VERSION 5.8 ;
BUSBITCHARS "[]" ;
DIVIDERCHAR "/" ;
UNITS
    DATABASE MICRONS 1000 ;
END UNITS

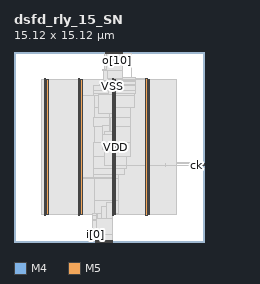
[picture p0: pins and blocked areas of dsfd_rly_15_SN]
MACRO dsfd_rly_15_SN
  FOREIGN dsfd_rly_15_SN 0 0 ;
  CLASS BLOCK ;
  SIZE 15.12 BY 15.12 ;
  PIN ck
    DIRECTION INPUT ;
    USE SIGNAL ;
    PORT
      LAYER M4 ;
        RECT  15.036 6.096 15.12 6.12 ;
    END
  END ck
  PIN i[0]
    DIRECTION INPUT ;
    USE SIGNAL ;
    PORT
      LAYER M5 ;
        RECT  6.48 0 6.504 0.084 ;
    END
  END i[0]
  PIN i[10]
    DIRECTION INPUT ;
    USE SIGNAL ;
    PORT
      LAYER M5 ;
        RECT  7.44 0 7.464 0.084 ;
    END
  END i[10]
  PIN i[11]
    DIRECTION INPUT ;
    USE SIGNAL ;
    PORT
      LAYER M5 ;
        RECT  7.536 0 7.56 0.084 ;
    END
  END i[11]
  PIN i[12]
    DIRECTION INPUT ;
    USE SIGNAL ;
    PORT
      LAYER M5 ;
        RECT  7.632 0 7.656 0.084 ;
    END
  END i[12]
  PIN i[13]
    DIRECTION INPUT ;
    USE SIGNAL ;
    PORT
      LAYER M5 ;
        RECT  7.728 0 7.752 0.084 ;
    END
  END i[13]
  PIN i[14]
    DIRECTION INPUT ;
    USE SIGNAL ;
    PORT
      LAYER M5 ;
        RECT  7.824 0 7.848 0.084 ;
    END
  END i[14]
  PIN i[1]
    DIRECTION INPUT ;
    USE SIGNAL ;
    PORT
      LAYER M5 ;
        RECT  6.576 0 6.6 0.084 ;
    END
  END i[1]
  PIN i[2]
    DIRECTION INPUT ;
    USE SIGNAL ;
    PORT
      LAYER M5 ;
        RECT  6.672 0 6.696 0.084 ;
    END
  END i[2]
  PIN i[3]
    DIRECTION INPUT ;
    USE SIGNAL ;
    PORT
      LAYER M5 ;
        RECT  6.768 0 6.792 0.084 ;
    END
  END i[3]
  PIN i[4]
    DIRECTION INPUT ;
    USE SIGNAL ;
    PORT
      LAYER M5 ;
        RECT  6.864 0 6.888 0.084 ;
    END
  END i[4]
  PIN i[5]
    DIRECTION INPUT ;
    USE SIGNAL ;
    PORT
      LAYER M5 ;
        RECT  6.96 0 6.984 0.084 ;
    END
  END i[5]
  PIN i[6]
    DIRECTION INPUT ;
    USE SIGNAL ;
    PORT
      LAYER M5 ;
        RECT  7.056 0 7.08 0.084 ;
    END
  END i[6]
  PIN i[7]
    DIRECTION INPUT ;
    USE SIGNAL ;
    PORT
      LAYER M5 ;
        RECT  7.152 0 7.176 0.084 ;
    END
  END i[7]
  PIN i[8]
    DIRECTION INPUT ;
    USE SIGNAL ;
    PORT
      LAYER M5 ;
        RECT  7.248 0 7.272 0.084 ;
    END
  END i[8]
  PIN i[9]
    DIRECTION INPUT ;
    USE SIGNAL ;
    PORT
      LAYER M5 ;
        RECT  7.344 0 7.368 0.084 ;
    END
  END i[9]
  PIN o[0]
    DIRECTION OUTPUT ;
    USE SIGNAL ;
    PORT
      LAYER M5 ;
        RECT  7.248 15.036 7.272 15.12 ;
    END
  END o[0]
  PIN o[10]
    DIRECTION OUTPUT ;
    USE SIGNAL ;
    PORT
      LAYER M5 ;
        RECT  8.208 15.036 8.232 15.12 ;
    END
  END o[10]
  PIN o[11]
    DIRECTION OUTPUT ;
    USE SIGNAL ;
    PORT
      LAYER M5 ;
        RECT  8.304 15.036 8.328 15.12 ;
    END
  END o[11]
  PIN o[12]
    DIRECTION OUTPUT ;
    USE SIGNAL ;
    PORT
      LAYER M5 ;
        RECT  8.4 15.036 8.424 15.12 ;
    END
  END o[12]
  PIN o[13]
    DIRECTION OUTPUT ;
    USE SIGNAL ;
    PORT
      LAYER M5 ;
        RECT  8.496 15.036 8.52 15.12 ;
    END
  END o[13]
  PIN o[14]
    DIRECTION OUTPUT ;
    USE SIGNAL ;
    PORT
      LAYER M5 ;
        RECT  8.592 15.036 8.616 15.12 ;
    END
  END o[14]
  PIN o[1]
    DIRECTION OUTPUT ;
    USE SIGNAL ;
    PORT
      LAYER M5 ;
        RECT  7.344 15.036 7.368 15.12 ;
    END
  END o[1]
  PIN o[2]
    DIRECTION OUTPUT ;
    USE SIGNAL ;
    PORT
      LAYER M5 ;
        RECT  7.44 15.036 7.464 15.12 ;
    END
  END o[2]
  PIN o[3]
    DIRECTION OUTPUT ;
    USE SIGNAL ;
    PORT
      LAYER M5 ;
        RECT  7.536 15.036 7.56 15.12 ;
    END
  END o[3]
  PIN o[4]
    DIRECTION OUTPUT ;
    USE SIGNAL ;
    PORT
      LAYER M5 ;
        RECT  7.632 15.036 7.656 15.12 ;
    END
  END o[4]
  PIN o[5]
    DIRECTION OUTPUT ;
    USE SIGNAL ;
    PORT
      LAYER M5 ;
        RECT  7.728 15.036 7.752 15.12 ;
    END
  END o[5]
  PIN o[6]
    DIRECTION OUTPUT ;
    USE SIGNAL ;
    PORT
      LAYER M5 ;
        RECT  7.824 15.036 7.848 15.12 ;
    END
  END o[6]
  PIN o[7]
    DIRECTION OUTPUT ;
    USE SIGNAL ;
    PORT
      LAYER M5 ;
        RECT  7.92 15.036 7.944 15.12 ;
    END
  END o[7]
  PIN o[8]
    DIRECTION OUTPUT ;
    USE SIGNAL ;
    PORT
      LAYER M5 ;
        RECT  8.016 15.036 8.04 15.12 ;
    END
  END o[8]
  PIN o[9]
    DIRECTION OUTPUT ;
    USE SIGNAL ;
    PORT
      LAYER M5 ;
        RECT  8.112 15.036 8.136 15.12 ;
    END
  END o[9]
  PIN rs
    DIRECTION INPUT ;
    USE SIGNAL ;
    PORT
      LAYER M4 ;
        RECT  15.036 6.192 15.12 6.216 ;
    END
  END rs
  PIN VDD
    DIRECTION INOUT ;
    USE POWER ;
    PORT
      LAYER M5 ;
        RECT  10.692 2.151 10.812 12.969 ;
        RECT  7.992 2.151 8.112 12.969 ;
        RECT  5.292 2.151 5.412 12.969 ;
        RECT  2.592 2.151 2.712 12.969 ;
    END
  END VDD
  PIN VSS
    DIRECTION INOUT ;
    USE GROUND ;
    PORT
      LAYER M5 ;
        RECT  10.5 2.137 10.62 12.983 ;
        RECT  7.8 2.137 7.92 12.983 ;
        RECT  5.1 2.137 5.22 12.983 ;
        RECT  2.4 2.137 2.52 12.983 ;
    END
  END VSS
  OBS
    LAYER RVTN ;
     RECT  2.16 2.16 12.96 2.295 ;
     RECT  2.16 2.565 12.96 2.835 ;
     RECT  2.16 3.105 12.96 3.375 ;
     RECT  2.16 3.645 12.96 3.915 ;
     RECT  2.16 4.185 12.96 4.455 ;
     RECT  2.16 4.725 12.96 4.995 ;
     RECT  2.16 5.265 12.96 5.535 ;
     RECT  2.16 5.805 12.96 6.075 ;
     RECT  2.16 6.345 12.96 6.615 ;
     RECT  2.16 6.885 12.96 7.155 ;
     RECT  2.16 7.425 12.96 7.695 ;
     RECT  2.16 7.965 12.96 8.235 ;
     RECT  2.16 8.505 12.96 8.775 ;
     RECT  2.16 9.045 12.96 9.315 ;
     RECT  2.16 9.585 12.96 9.855 ;
     RECT  2.16 10.125 12.96 10.395 ;
     RECT  2.16 10.665 12.96 10.935 ;
     RECT  2.16 11.205 12.96 11.475 ;
     RECT  2.16 11.745 12.96 12.015 ;
     RECT  2.16 12.285 12.96 12.555 ;
     RECT  2.16 12.825 12.96 12.96 ;
    LAYER RVTP ;
     RECT  2.16 2.295 12.96 2.565 ;
     RECT  2.16 2.835 12.96 3.105 ;
     RECT  2.16 3.375 12.96 3.645 ;
     RECT  2.16 3.915 12.96 4.185 ;
     RECT  2.16 4.455 12.96 4.725 ;
     RECT  2.16 4.995 12.96 5.265 ;
     RECT  2.16 5.535 12.96 5.805 ;
     RECT  2.16 6.075 12.96 6.345 ;
     RECT  2.16 6.615 12.96 6.885 ;
     RECT  2.16 7.155 12.96 7.425 ;
     RECT  2.16 7.695 12.96 7.965 ;
     RECT  2.16 8.235 12.96 8.505 ;
     RECT  2.16 8.775 12.96 9.045 ;
     RECT  2.16 9.315 12.96 9.585 ;
     RECT  2.16 9.855 12.96 10.125 ;
     RECT  2.16 10.395 12.96 10.665 ;
     RECT  2.16 10.935 12.96 11.205 ;
     RECT  2.16 11.475 12.96 11.745 ;
     RECT  2.16 12.015 12.96 12.285 ;
     RECT  2.16 12.555 12.96 12.825 ;
    LAYER M1 ;
     RECT  2.16 2.151 12.96 12.969 ;
    LAYER M2 ;
     RECT  2.16 2.151 12.96 12.969 ;
     RECT  12.96 6.282 14.243 6.3 ;
    LAYER M3 ;
     RECT  7.2 0.091 7.218 0.571 ;
     RECT  6.264 0.571 7.218 1.723 ;
     RECT  6.264 1.723 7.758 1.819 ;
     RECT  6.264 1.819 7.794 2.143 ;
     RECT  6.264 2.143 7.905 2.255 ;
     RECT  6.408 2.255 7.905 2.263 ;
     RECT  2.415 2.143 2.505 2.413 ;
     RECT  5.115 2.143 5.205 2.413 ;
     RECT  10.515 2.143 10.605 2.413 ;
     RECT  6.408 2.263 8.298 3.335 ;
     RECT  6.444 3.335 8.298 5.035 ;
     RECT  6.3 5.035 8.298 5.341 ;
     RECT  6.3 5.341 8.766 5.881 ;
     RECT  12.024 6.007 12.042 6.269 ;
     RECT  14.22 6.187 14.238 6.305 ;
     RECT  6.3 5.881 8.982 6.817 ;
     RECT  6.3 6.817 9.306 7.925 ;
     RECT  6.444 7.925 9.306 9.211 ;
     RECT  6.336 9.211 9.306 9.923 ;
     RECT  6.372 9.923 9.306 10.741 ;
     RECT  6.372 10.741 9.594 11.659 ;
     RECT  6.3 11.659 9.594 11.821 ;
     RECT  6.3 11.821 9.666 12.083 ;
     RECT  6.336 12.083 9.666 12.479 ;
     RECT  6.768 12.479 9.666 12.551 ;
     RECT  2.415 2.413 2.697 12.707 ;
     RECT  5.115 2.413 5.397 12.707 ;
     RECT  10.515 2.413 10.797 12.707 ;
     RECT  6.912 12.551 9.666 12.785 ;
     RECT  7.092 12.785 9.666 12.857 ;
     RECT  9.324 12.857 9.666 12.901 ;
     RECT  2.415 12.707 2.505 12.977 ;
     RECT  5.115 12.707 5.205 12.977 ;
     RECT  10.515 12.707 10.605 12.977 ;
     RECT  9.324 12.901 9.702 12.989 ;
     RECT  9.324 12.989 9.666 13.085 ;
     RECT  7.092 12.857 8.586 13.661 ;
     RECT  7.092 13.661 7.722 13.709 ;
     RECT  8.568 13.661 8.586 14.957 ;
     RECT  7.2 13.709 7.722 15.005 ;
     RECT  9.324 13.085 9.342 15.005 ;
    LAYER M4 ;
     RECT  2.408 2.148 2.512 12.972 ;
     RECT  2.512 2.418 2.704 12.702 ;
     RECT  5.108 2.148 5.212 12.972 ;
     RECT  5.212 2.418 5.404 12.702 ;
     RECT  6.397 2.256 6.649 2.28 ;
     RECT  5.404 11.664 6.755 11.688 ;
     RECT  6.709 10.224 6.797 10.248 ;
     RECT  6.649 1.728 6.973 2.28 ;
     RECT  6.253 0.576 6.995 0.6 ;
     RECT  7.009 9.216 7.045 9.24 ;
     RECT  7.189 6.096 7.225 6.12 ;
     RECT  7.004 7.344 7.225 7.368 ;
     RECT  6.973 1.728 7.333 2.856 ;
     RECT  7.081 13.68 7.379 13.704 ;
     RECT  7.189 0.096 7.475 0.12 ;
     RECT  7.189 14.976 7.525 15 ;
     RECT  7.045 8.544 7.621 9.24 ;
     RECT  7.333 1.728 7.804 3.144 ;
     RECT  7.804 1.824 7.808 3.144 ;
     RECT  5.404 5.088 7.808 5.112 ;
     RECT  7.225 6.096 7.808 7.368 ;
     RECT  7.621 8.544 7.808 9.912 ;
     RECT  7.525 11.232 7.808 11.448 ;
     RECT  7.405 13.056 7.808 13.656 ;
     RECT  7.808 1.824 7.859 13.656 ;
     RECT  7.859 2.148 7.912 13.656 ;
     RECT  7.525 14.736 7.955 15 ;
     RECT  7.912 2.418 8.104 13.656 ;
     RECT  8.104 12.816 8.345 13.656 ;
     RECT  8.345 12.816 8.489 13.608 ;
     RECT  8.489 12.816 8.561 13.08 ;
     RECT  7.955 14.928 8.597 15 ;
     RECT  8.597 14.976 9.353 15 ;
     RECT  8.561 12.96 9.677 13.08 ;
     RECT  9.677 12.96 9.713 12.984 ;
     RECT  8.104 6.096 10.508 6.12 ;
     RECT  9.713 12.96 10.508 12.972 ;
     RECT  10.508 2.148 10.612 12.972 ;
     RECT  10.612 2.418 10.804 12.702 ;
     RECT  10.804 6.096 14.209 6.12 ;
     RECT  14.209 6.096 15.084 6.216 ;
    LAYER M5 ;
     RECT  6.48 0.016 7.848 0.611 ;
     RECT  6.576 0.611 7.848 1.907 ;
     RECT  7.8 1.907 7.848 2.137 ;
     RECT  2.4 2.137 2.52 2.151 ;
     RECT  5.1 2.137 5.22 2.151 ;
     RECT  7.8 2.137 7.92 2.151 ;
     RECT  10.5 2.137 10.62 2.151 ;
     RECT  6.576 1.907 6.6 2.291 ;
     RECT  7.8 2.151 8.112 6.085 ;
     RECT  7.2 6.085 8.112 7.333 ;
     RECT  7.056 7.333 8.112 8.579 ;
     RECT  7.2 8.579 8.112 8.771 ;
     RECT  7.68 8.771 8.112 9.877 ;
     RECT  7.632 9.877 8.112 10.213 ;
     RECT  6.72 10.213 8.112 11.699 ;
     RECT  7.536 11.699 8.112 12.949 ;
     RECT  2.4 2.151 2.712 12.969 ;
     RECT  5.1 2.151 5.412 12.969 ;
     RECT  10.5 2.151 10.812 12.969 ;
     RECT  2.4 12.969 2.52 12.983 ;
     RECT  5.1 12.969 5.22 12.983 ;
     RECT  10.5 12.969 10.62 12.983 ;
     RECT  7.536 12.949 8.616 13.045 ;
     RECT  7.44 13.045 8.616 13.669 ;
     RECT  7.344 13.669 8.616 14.965 ;
     RECT  7.248 14.965 8.616 15.056 ;
  END
END dsfd_rly_15_SN
END LIBRARY
